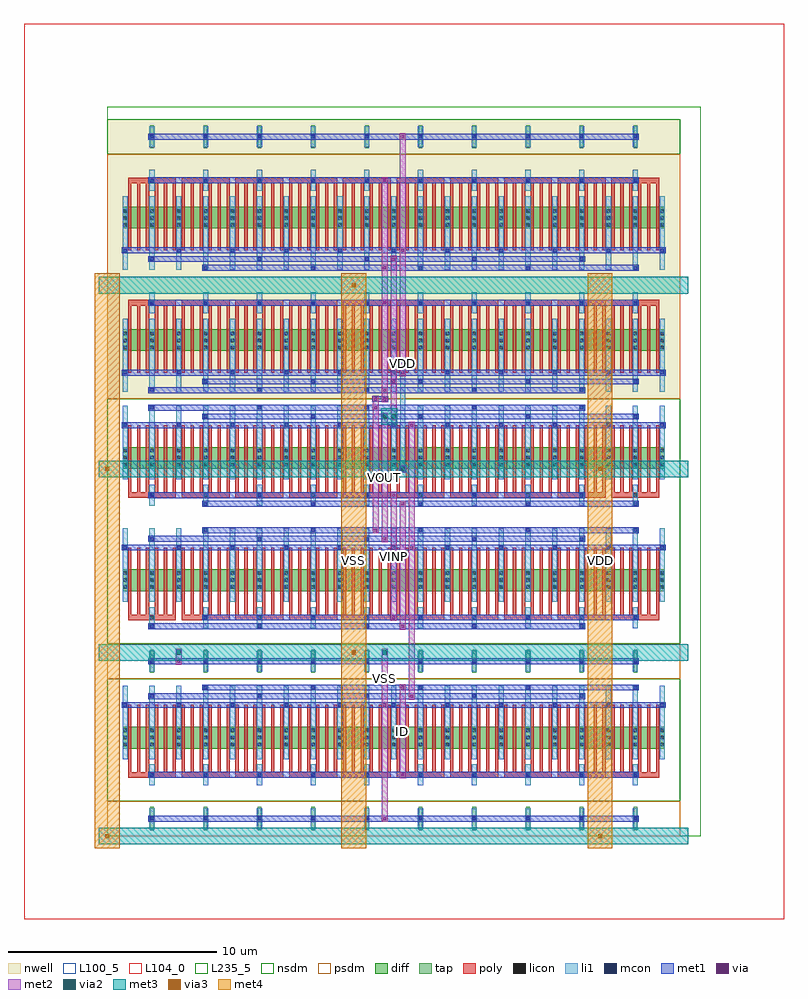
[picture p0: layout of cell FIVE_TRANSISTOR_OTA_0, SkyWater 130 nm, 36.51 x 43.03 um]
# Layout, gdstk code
from math import pi, radians
import gdstk
lib = gdstk.Library(unit=1e-6, precision=1e-09)
def R(c, l, rs):  # rectangles x0, y0, x1, y1
    for r in rs: c.add(gdstk.rectangle(r[:2], r[2:], *l))
def A(c, l, x, y, w, h, nx, ny, dx, dy):  # array of equal rectangles
    R(c, l, [(x+i*dx, y+j*dy, x+i*dx+w, y+j*dy+h) for i in range(nx) for j in range(ny)])
def P(c, l, *ps):  # polygons
    for p in ps: c.add(gdstk.Polygon(p, *l))
nwell = (64, 20)
diff = (65, 20)
tap = (65, 44)
poly = (66, 20)
licon = (66, 44)
li1 = (67, 20)
mcon = (67, 44)
met1 = (68, 20)
via = (68, 44)
met2 = (69, 20)
via2 = (69, 44)
met3 = (70, 20)
via3 = (70, 44)
met4 = (71, 20)
nsdm = (93, 44)
psdm = (94, 20)
L100_5 = (100, 5)
L104_0 = (104, 0)
L235_5 = (235, 5)

scm_nmos_50859816_x5_y1_ = lib.new_cell('SCM_NMOS_50859816_X5_Y1_1676474433')
R(scm_nmos_50859816_x5_y1_, diff, [(0.735,2.31,26.785,3.36)])
A(scm_nmos_50859816_x5_y1_, tap, 2.065, 6.16, 0.17, 1.12, 10, 1, 2.58, 0)
A(scm_nmos_50859816_x5_y1_, poly, 1, 1.26, 0.15, 3.36, 60, 1, 0.43, 0)
A(scm_nmos_50859816_x5_y1_, poly, 1, 4.485, 2.3, 0.27, 10, 1, 2.58, 0)
A(scm_nmos_50859816_x5_y1_, licon, 0.775, 2.39, 0.17, 0.17, 3, 3, 1.29, 0.34)
A(scm_nmos_50859816_x5_y1_, licon, 3.355, 2.39, 0.17, 0.17, 3, 3, 1.29, 0.34)
A(scm_nmos_50859816_x5_y1_, licon, 5.935, 2.39, 0.17, 0.17, 3, 3, 1.29, 0.34)
A(scm_nmos_50859816_x5_y1_, licon, 8.515, 2.39, 0.17, 0.17, 3, 3, 1.29, 0.34)
A(scm_nmos_50859816_x5_y1_, licon, 11.095, 2.39, 0.17, 0.17, 3, 3, 1.29, 0.34)
A(scm_nmos_50859816_x5_y1_, licon, 13.675, 2.39, 0.17, 0.17, 3, 3, 1.29, 0.34)
A(scm_nmos_50859816_x5_y1_, licon, 16.255, 2.39, 0.17, 0.17, 3, 3, 1.29, 0.34)
A(scm_nmos_50859816_x5_y1_, licon, 18.835, 2.39, 0.17, 0.17, 3, 3, 1.29, 0.34)
A(scm_nmos_50859816_x5_y1_, licon, 21.415, 2.39, 0.17, 0.17, 3, 3, 1.29, 0.34)
A(scm_nmos_50859816_x5_y1_, licon, 23.995, 2.39, 0.17, 0.17, 3, 3, 1.29, 0.34)
A(scm_nmos_50859816_x5_y1_, licon, 2.065, 4.535, 0.17, 0.17, 10, 2, 2.58, 2.1)
A(scm_nmos_50859816_x5_y1_, li1, 0.735, 0.335, 0.25, 3.53, 21, 1, 1.29, 0)
A(scm_nmos_50859816_x5_y1_, li1, 2.025, 4.115, 0.25, 1.01, 10, 2, 2.58, 2.1)
A(scm_nmos_50859816_x5_y1_, mcon, 2.065, 0.335, 0.17, 0.17, 5, 1, 5.16, 0)
A(scm_nmos_50859816_x5_y1_, mcon, 4.645, 0.755, 0.17, 0.17, 5, 1, 5.16, 0)
A(scm_nmos_50859816_x5_y1_, mcon, 0.775, 1.175, 0.17, 0.17, 11, 1, 2.58, 0)
A(scm_nmos_50859816_x5_y1_, mcon, 2.065, 4.535, 0.17, 0.17, 10, 2, 2.58, 2.1)
R(scm_nmos_50859816_x5_y1_, met1, [(1.98,0.28,22.96,0.56), (4.56,0.7,25.54,0.98), (0.69,1.12,26.83,1.4), (1.98,4.48,25.54,4.76), (1.98,6.58,25.54,6.86)])
R(scm_nmos_50859816_x5_y1_, via, [(13.255,0.345,13.405,0.495), (14.115,1.185,14.265,1.335), (13.255,4.545,13.405,4.695), (14.115,6.645,14.265,6.795)])
R(scm_nmos_50859816_x5_y1_, met2, [(13.19,0.26,13.47,4.78), (14.05,1.1,14.33,6.88)])
R(scm_nmos_50859816_x5_y1_, nsdm, [(0,0,27.52,5.88)])
R(scm_nmos_50859816_x5_y1_, psdm, [(0,5.88,27.52,7.56)])
R(scm_nmos_50859816_x5_y1_, L100_5, [(0,0,27.52,7.56)])

scm_pmos_24041719_x5_y2_ = lib.new_cell('SCM_PMOS_24041719_X5_Y2_1676474434')
R(scm_pmos_24041719_x5_y2_, nwell, [(0,0,27.52,13.44)])
R(scm_pmos_24041719_x5_y2_, diff, [(0.735,2.31,26.785,3.36), (0.735,8.19,26.785,9.24)])
A(scm_pmos_24041719_x5_y2_, tap, 2.065, 12.04, 0.17, 1.12, 10, 1, 2.58, 0)
A(scm_pmos_24041719_x5_y2_, poly, 1, 1.26, 0.15, 3.36, 60, 2, 0.43, 5.88)
A(scm_pmos_24041719_x5_y2_, poly, 1, 4.485, 2.3, 0.27, 10, 2, 2.58, 5.88)
A(scm_pmos_24041719_x5_y2_, licon, 0.775, 2.39, 0.17, 0.17, 3, 3, 1.29, 0.34)
A(scm_pmos_24041719_x5_y2_, licon, 3.355, 2.39, 0.17, 0.17, 3, 3, 1.29, 0.34)
A(scm_pmos_24041719_x5_y2_, licon, 5.935, 2.39, 0.17, 0.17, 3, 3, 1.29, 0.34)
A(scm_pmos_24041719_x5_y2_, licon, 8.515, 2.39, 0.17, 0.17, 3, 3, 1.29, 0.34)
A(scm_pmos_24041719_x5_y2_, licon, 11.095, 2.39, 0.17, 0.17, 3, 3, 1.29, 0.34)
A(scm_pmos_24041719_x5_y2_, licon, 13.675, 2.39, 0.17, 0.17, 3, 3, 1.29, 0.34)
A(scm_pmos_24041719_x5_y2_, licon, 16.255, 2.39, 0.17, 0.17, 3, 3, 1.29, 0.34)
A(scm_pmos_24041719_x5_y2_, licon, 18.835, 2.39, 0.17, 0.17, 3, 3, 1.29, 0.34)
A(scm_pmos_24041719_x5_y2_, licon, 21.415, 2.39, 0.17, 0.17, 3, 3, 1.29, 0.34)
A(scm_pmos_24041719_x5_y2_, licon, 23.995, 2.39, 0.17, 0.17, 3, 3, 1.29, 0.34)
A(scm_pmos_24041719_x5_y2_, licon, 2.065, 4.535, 0.17, 0.17, 10, 2, 2.58, 5.88)
A(scm_pmos_24041719_x5_y2_, licon, 0.775, 8.27, 0.17, 0.17, 3, 3, 1.29, 0.34)
A(scm_pmos_24041719_x5_y2_, licon, 3.355, 8.27, 0.17, 0.17, 3, 3, 1.29, 0.34)
A(scm_pmos_24041719_x5_y2_, licon, 5.935, 8.27, 0.17, 0.17, 3, 3, 1.29, 0.34)
A(scm_pmos_24041719_x5_y2_, licon, 8.515, 8.27, 0.17, 0.17, 3, 3, 1.29, 0.34)
A(scm_pmos_24041719_x5_y2_, licon, 11.095, 8.27, 0.17, 0.17, 3, 3, 1.29, 0.34)
A(scm_pmos_24041719_x5_y2_, licon, 13.675, 8.27, 0.17, 0.17, 3, 3, 1.29, 0.34)
A(scm_pmos_24041719_x5_y2_, licon, 16.255, 8.27, 0.17, 0.17, 3, 3, 1.29, 0.34)
A(scm_pmos_24041719_x5_y2_, licon, 18.835, 8.27, 0.17, 0.17, 3, 3, 1.29, 0.34)
A(scm_pmos_24041719_x5_y2_, licon, 21.415, 8.27, 0.17, 0.17, 3, 3, 1.29, 0.34)
A(scm_pmos_24041719_x5_y2_, licon, 23.995, 8.27, 0.17, 0.17, 3, 3, 1.29, 0.34)
R(scm_pmos_24041719_x5_y2_, licon, [(2.065,12.515,2.235,12.685), (2.065,12.515,2.235,12.685), (4.645,12.515,4.815,12.685), (4.645,12.515,4.815,12.685), (7.225,12.515,7.395,12.685), (7.225,12.515,7.395,12.685), (9.805,12.515,9.975,12.685), (9.805,12.515,9.975,12.685), (12.385,12.515,12.555,12.685), (12.385,12.515,12.555,12.685), (14.965,12.515,15.135,12.685), (14.965,12.515,15.135,12.685), (17.545,12.515,17.715,12.685), (17.545,12.515,17.715,12.685), (20.125,12.515,20.295,12.685), (20.125,12.515,20.295,12.685), (22.705,12.515,22.875,12.685), (22.705,12.515,22.875,12.685), (25.285,12.515,25.455,12.685), (25.285,12.515,25.455,12.685)])
A(scm_pmos_24041719_x5_y2_, li1, 0.735, 0.335, 0.25, 3.53, 21, 2, 1.29, 5.88)
A(scm_pmos_24041719_x5_y2_, li1, 2.025, 4.115, 0.25, 1.01, 10, 2, 2.58, 5.88)
A(scm_pmos_24041719_x5_y2_, li1, 2.025, 12.095, 0.25, 1.01, 10, 1, 2.58, 0)
A(scm_pmos_24041719_x5_y2_, mcon, 2.065, 0.335, 0.17, 0.17, 5, 2, 5.16, 6.3)
A(scm_pmos_24041719_x5_y2_, mcon, 4.645, 0.755, 0.17, 0.17, 5, 2, 5.16, 5.46)
A(scm_pmos_24041719_x5_y2_, mcon, 0.775, 1.175, 0.17, 0.17, 11, 2, 2.58, 5.88)
A(scm_pmos_24041719_x5_y2_, mcon, 2.065, 4.535, 0.17, 0.17, 10, 2, 2.58, 5.88)
A(scm_pmos_24041719_x5_y2_, mcon, 2.065, 12.515, 0.17, 0.17, 10, 1, 2.58, 0)
R(scm_pmos_24041719_x5_y2_, met1, [(1.98,0.28,22.96,0.56), (4.56,0.7,25.54,0.98), (0.69,1.12,26.83,1.4), (1.98,4.48,25.54,4.76), (4.56,6.16,25.54,6.44), (1.98,6.58,22.96,6.86), (0.69,7,26.83,7.28), (1.98,10.36,25.54,10.64), (1.98,12.46,25.54,12.74)])
R(scm_pmos_24041719_x5_y2_, via, [(13.255,0.345,13.405,0.495), (13.685,0.765,13.835,0.915), (14.115,1.185,14.265,1.335), (13.255,4.545,13.405,4.695), (13.255,6.225,13.405,6.375), (13.685,6.645,13.835,6.795), (14.115,7.065,14.265,7.215), (13.255,10.425,13.405,10.575), (14.115,12.525,14.265,12.675)])
R(scm_pmos_24041719_x5_y2_, met2, [(13.19,0.26,13.47,10.66), (13.62,0.68,13.9,6.88), (14.05,1.1,14.33,12.76)])
R(scm_pmos_24041719_x5_y2_, nsdm, [(0,11.76,27.52,13.44)])
R(scm_pmos_24041719_x5_y2_, psdm, [(0,0,27.52,11.76)])
R(scm_pmos_24041719_x5_y2_, L100_5, [(0,0,27.52,13.44)])

dp_nmos_b_62677564_x5_y2 = lib.new_cell('DP_NMOS_B_62677564_X5_Y2_1676474432')
R(dp_nmos_b_62677564_x5_y2, diff, [(0.735,2.31,26.785,3.36), (0.735,8.19,26.785,9.24)])
A(dp_nmos_b_62677564_x5_y2, tap, 2.065, 12.04, 0.17, 1.12, 10, 1, 2.58, 0)
A(dp_nmos_b_62677564_x5_y2, poly, 1, 1.26, 0.15, 3.36, 60, 2, 0.43, 5.88)
A(dp_nmos_b_62677564_x5_y2, poly, 1, 4.485, 2.3, 0.27, 10, 2, 2.58, 5.88)
A(dp_nmos_b_62677564_x5_y2, licon, 0.775, 2.39, 0.17, 0.17, 3, 3, 1.29, 0.34)
A(dp_nmos_b_62677564_x5_y2, licon, 3.355, 2.39, 0.17, 0.17, 3, 3, 1.29, 0.34)
A(dp_nmos_b_62677564_x5_y2, licon, 5.935, 2.39, 0.17, 0.17, 3, 3, 1.29, 0.34)
A(dp_nmos_b_62677564_x5_y2, licon, 8.515, 2.39, 0.17, 0.17, 3, 3, 1.29, 0.34)
A(dp_nmos_b_62677564_x5_y2, licon, 11.095, 2.39, 0.17, 0.17, 3, 3, 1.29, 0.34)
A(dp_nmos_b_62677564_x5_y2, licon, 13.675, 2.39, 0.17, 0.17, 3, 3, 1.29, 0.34)
A(dp_nmos_b_62677564_x5_y2, licon, 16.255, 2.39, 0.17, 0.17, 3, 3, 1.29, 0.34)
A(dp_nmos_b_62677564_x5_y2, licon, 18.835, 2.39, 0.17, 0.17, 3, 3, 1.29, 0.34)
A(dp_nmos_b_62677564_x5_y2, licon, 21.415, 2.39, 0.17, 0.17, 3, 3, 1.29, 0.34)
A(dp_nmos_b_62677564_x5_y2, licon, 23.995, 2.39, 0.17, 0.17, 3, 3, 1.29, 0.34)
A(dp_nmos_b_62677564_x5_y2, licon, 2.065, 4.535, 0.17, 0.17, 10, 2, 2.58, 5.88)
A(dp_nmos_b_62677564_x5_y2, licon, 0.775, 8.27, 0.17, 0.17, 3, 3, 1.29, 0.34)
A(dp_nmos_b_62677564_x5_y2, licon, 3.355, 8.27, 0.17, 0.17, 3, 3, 1.29, 0.34)
A(dp_nmos_b_62677564_x5_y2, licon, 5.935, 8.27, 0.17, 0.17, 3, 3, 1.29, 0.34)
A(dp_nmos_b_62677564_x5_y2, licon, 8.515, 8.27, 0.17, 0.17, 3, 3, 1.29, 0.34)
A(dp_nmos_b_62677564_x5_y2, licon, 11.095, 8.27, 0.17, 0.17, 3, 3, 1.29, 0.34)
A(dp_nmos_b_62677564_x5_y2, licon, 13.675, 8.27, 0.17, 0.17, 3, 3, 1.29, 0.34)
A(dp_nmos_b_62677564_x5_y2, licon, 16.255, 8.27, 0.17, 0.17, 3, 3, 1.29, 0.34)
A(dp_nmos_b_62677564_x5_y2, licon, 18.835, 8.27, 0.17, 0.17, 3, 3, 1.29, 0.34)
A(dp_nmos_b_62677564_x5_y2, licon, 21.415, 8.27, 0.17, 0.17, 3, 3, 1.29, 0.34)
A(dp_nmos_b_62677564_x5_y2, licon, 23.995, 8.27, 0.17, 0.17, 3, 3, 1.29, 0.34)
R(dp_nmos_b_62677564_x5_y2, licon, [(2.065,12.515,2.235,12.685), (2.065,12.515,2.235,12.685), (4.645,12.515,4.815,12.685), (4.645,12.515,4.815,12.685), (7.225,12.515,7.395,12.685), (7.225,12.515,7.395,12.685), (9.805,12.515,9.975,12.685), (9.805,12.515,9.975,12.685), (12.385,12.515,12.555,12.685), (12.385,12.515,12.555,12.685), (14.965,12.515,15.135,12.685), (14.965,12.515,15.135,12.685), (17.545,12.515,17.715,12.685), (17.545,12.515,17.715,12.685), (20.125,12.515,20.295,12.685), (20.125,12.515,20.295,12.685), (22.705,12.515,22.875,12.685), (22.705,12.515,22.875,12.685), (25.285,12.515,25.455,12.685), (25.285,12.515,25.455,12.685)])
A(dp_nmos_b_62677564_x5_y2, li1, 0.735, 0.335, 0.25, 3.53, 21, 2, 1.29, 5.88)
A(dp_nmos_b_62677564_x5_y2, li1, 2.025, 4.115, 0.25, 1.01, 10, 2, 2.58, 5.88)
A(dp_nmos_b_62677564_x5_y2, li1, 2.025, 12.095, 0.25, 1.01, 10, 1, 2.58, 0)
A(dp_nmos_b_62677564_x5_y2, mcon, 2.065, 0.335, 0.17, 0.17, 5, 2, 5.16, 4.2)
A(dp_nmos_b_62677564_x5_y2, mcon, 4.645, 0.755, 0.17, 0.17, 5, 2, 5.16, 4.2)
A(dp_nmos_b_62677564_x5_y2, mcon, 0.775, 1.175, 0.17, 0.17, 11, 2, 2.58, 5.88)
A(dp_nmos_b_62677564_x5_y2, mcon, 4.645, 6.215, 0.17, 0.17, 5, 2, 5.16, 4.2)
A(dp_nmos_b_62677564_x5_y2, mcon, 2.065, 6.635, 0.17, 0.17, 5, 2, 5.16, 4.2)
A(dp_nmos_b_62677564_x5_y2, mcon, 2.065, 12.515, 0.17, 0.17, 10, 1, 2.58, 0)
R(dp_nmos_b_62677564_x5_y2, met1, [(1.98,0.28,22.96,0.56), (4.56,0.7,25.54,0.98), (0.69,1.12,26.83,1.4), (1.98,4.48,22.96,4.76), (4.56,4.9,25.54,5.18), (4.56,6.16,25.54,6.44), (1.98,6.58,22.96,6.86), (0.69,7,26.83,7.28), (4.56,10.36,25.54,10.64), (1.98,10.78,22.96,11.06), (1.98,12.46,25.54,12.74)])
R(dp_nmos_b_62677564_x5_y2, via, [(12.825,0.345,12.975,0.495), (13.255,0.765,13.405,0.915), (14.545,1.185,14.695,1.335), (13.685,4.545,13.835,4.695), (14.115,4.965,14.265,5.115), (12.825,6.225,12.975,6.375), (13.255,6.645,13.405,6.795), (14.545,7.065,14.695,7.215), (13.685,10.425,13.835,10.575), (14.115,10.845,14.265,10.995)])
R(dp_nmos_b_62677564_x5_y2, met2, [(12.76,0.26,13.04,6.46), (13.19,0.68,13.47,6.88), (14.48,1.1,14.76,7.3), (13.62,4.46,13.9,10.66), (14.05,4.88,14.33,11.08)])
R(dp_nmos_b_62677564_x5_y2, nsdm, [(0,0,27.52,11.76)])
R(dp_nmos_b_62677564_x5_y2, psdm, [(0,11.76,27.52,13.44)])
R(dp_nmos_b_62677564_x5_y2, L100_5, [(0,0,27.52,13.44)])

five_transistor_ota_0 = lib.new_cell('FIVE_TRANSISTOR_OTA_0')
R(five_transistor_ota_0, li1, [(14.065,17.555,14.315,17.725), (14.065,17.64,14.315,22.68), (14.065,22.595,14.315,22.765)])
R(five_transistor_ota_0, mcon, [(14.105,17.555,14.275,17.725), (14.105,22.595,14.275,22.765)])
R(five_transistor_ota_0, met1, [(14.46,6.58,14.78,6.86), (14.46,6.58,14.78,6.86), (3.28,8.26,3.6,8.54), (3.28,8.26,3.6,8.54), (14.02,17.5,14.36,17.78), (14.03,17.5,14.35,17.78), (14.041,17.5,14.339,17.78), (12.74,20.86,13.06,21.14), (12.74,20.86,13.06,21.14), (12.9,20.86,13.33,21.14), (13.17,20.86,13.49,21.14), (13.17,20.86,13.49,21.14), (14.02,22.54,14.36,22.82), (14.03,22.54,14.35,22.82), (14.041,22.54,14.339,22.82)])
P(five_transistor_ota_0, met1, [(0,0),(0,0),(0,0),(0,0)],
  [(0,0),(0,0),(0,0),(0,0)])
R(five_transistor_ota_0, via, [(14.545,6.645,14.695,6.795), (14.545,6.645,14.695,6.795), (3.365,8.325,3.515,8.475), (3.365,8.325,3.515,8.475), (14.115,17.565,14.265,17.715), (12.825,20.925,12.975,21.075), (12.825,20.925,12.975,21.075), (13.255,20.925,13.405,21.075), (13.255,20.925,13.405,21.075), (14.115,22.605,14.265,22.755)])
R(five_transistor_ota_0, met2, [(13.19,6.3,13.47,8.82), (14.48,6.56,14.76,6.88), (14.48,6.56,14.76,6.88), (14.48,6.72,14.76,13.86), (3.3,8.24,3.58,8.56), (3.3,8.24,3.58,8.56), (3.3,8.4,3.58,8.82), (3.3,8.635,3.58,9.005), (3.3,8.635,3.58,9.005), (13.19,8.635,13.47,9.005), (13.19,8.635,13.47,9.005), (13.19,8.635,13.47,9.005), (14.05,17.455,14.33,17.825), (14.05,17.48,14.33,17.8), (14.05,17.519,14.33,17.761), (13.19,19.975,13.47,20.345), (13.19,19.975,13.47,20.345), (13.62,19.975,13.9,20.345), (13.62,19.975,13.9,20.345), (13.62,20.16,13.9,21.84), (12.76,20.58,13.04,21), (12.76,20.84,13.04,21.16), (12.76,20.84,13.04,21.16), (13.19,20.84,13.47,21.16), (13.19,20.84,13.47,21.16), (13.19,21,13.47,21.42), (14.05,22.52,14.33,22.84)])
P(five_transistor_ota_0, met2, [(0,0),(0,0),(0,0),(0,0)],
  [(0,0),(0,0),(0,0),(0,0)],
  [(0,0),(0,0),(0,0),(0,0)],
  [(0,0),(0,0),(0,0),(0,0)],
  [(0,0),(0,0),(0,0),(0,0)],
  [(0,0),(0,0),(0,0),(0,0)],
  [(0,0),(0,0),(0,0),(0,0)],
  [(0,0),(0,0),(0,0),(0,0)],
  [(0,0),(0,0),(0,0),(0,0)],
  [(0,0),(0,0),(0,0),(0,0)],
  [(0,0),(0,0),(0,0),(0,0)],
  [(0,0),(0,0),(0,0),(0,0)],
  [(0,0),(0,0),(0,0),(0,0)],
  [(0,0),(0,0),(0,0),(0,0)])
R(five_transistor_ota_0, via2, [(3.34,8.72,3.54,8.92), (3.34,8.72,3.54,8.92), (13.23,8.72,13.43,8.92), (13.23,8.72,13.43,8.92), (13.23,8.72,13.43,8.92), (14.09,17.54,14.29,17.74), (13.23,20.06,13.43,20.26), (13.23,20.06,13.43,20.26), (13.66,20.06,13.86,20.26), (13.66,20.06,13.86,20.26)])
A(five_transistor_ota_0, met3, -0.4, -0.4, 4.24, 0.8, 3, 4, 3.44, 8.82)
A(five_transistor_ota_0, met3, 9.92, -0.4, 2.32, 0.8, 1, 4, 0, 8.82)
A(five_transistor_ota_0, met3, 11.44, -0.4, 2.72, 0.8, 1, 4, 0, 8.82)
A(five_transistor_ota_0, met3, 13.36, -0.4, 4.24, 0.8, 1, 4, 0, 8.82)
A(five_transistor_ota_0, met3, 16.8, -0.4, 4.24, 0.8, 1, 4, 0, 8.82)
A(five_transistor_ota_0, met3, 20.24, -0.4, 3.84, 0.8, 1, 4, 0, 8.82)
A(five_transistor_ota_0, met3, 23.28, -0.4, 1.2, 0.8, 1, 4, 0, 8.82)
A(five_transistor_ota_0, met3, 23.68, -0.4, 4.24, 0.8, 1, 4, 0, 8.82)
R(five_transistor_ota_0, met3, [(-0.165,-0.4,0.165,0.4), (23.515,-0.4,23.845,0.4), (3.275,8.42,3.605,9.22), (3.275,8.42,3.605,9.22), (11.675,8.42,12.005,9.22), (13.165,8.42,13.495,9.22), (13.165,8.42,13.495,9.22), (13.165,8.42,13.495,9.22), (-0.165,17.24,0.165,18.04), (14.025,17.24,14.355,18.04), (23.515,17.24,23.845,18.04), (13.165,19.76,13.495,20.56), (13.165,19.76,13.495,20.56), (13.33,19.76,13.76,20.56), (13.595,19.76,13.925,20.56), (13.595,19.76,13.925,20.56), (11.675,26.06,12.005,26.86)])
R(five_transistor_ota_0, via3, [(-0.1,-0.1,0.1,0.1), (23.58,-0.1,23.78,0.1), (11.74,8.72,11.94,8.92), (-0.1,17.54,0.1,17.74), (23.58,17.54,23.78,17.74), (11.74,26.36,11.94,26.56)])
A(five_transistor_ota_0, met4, -0.59, -0.59, 1.18, 10, 3, 3, 11.84, 8.82)
R(five_transistor_ota_0, met4, [(-0.59,-0.165,0.59,0.165), (23.09,-0.165,24.27,0.165), (11.25,8.655,12.43,8.985), (-0.59,17.475,0.59,17.805), (23.09,17.475,24.27,17.805), (11.25,26.295,12.43,26.625)])
R(five_transistor_ota_0, L104_0, [(-4,-4,32.51,39.03)])
R(five_transistor_ota_0, L235_5, [(0,0,28.51,35.03)])
five_transistor_ota_0.add(gdstk.Reference(scm_nmos_50859816_x5_y1_, (27.52,7.56), rotation=pi))
five_transistor_ota_0.add(gdstk.Reference(scm_pmos_24041719_x5_y2_, (0,21)))
five_transistor_ota_0.add(gdstk.Reference(dp_nmos_b_62677564_x5_y2, (0,21), x_reflection=True))
five_transistor_ota_0.add(gdstk.Label('ID', (14.19,5.04), layer=69, texttype=5))
five_transistor_ota_0.add(gdstk.Label('VOUT', (13.33,17.22), layer=69, texttype=5))
five_transistor_ota_0.add(gdstk.Label('VINP', (13.76,13.44), layer=69, texttype=5))
five_transistor_ota_0.add(gdstk.Label('VINN', (14.19,13.02), layer=69, texttype=5))
five_transistor_ota_0.add(gdstk.Label('VSS', (13.33,7.56), layer=69, texttype=5))
five_transistor_ota_0.add(gdstk.Label('VSS', (11.84,13.23), layer=71, texttype=5))
five_transistor_ota_0.add(gdstk.Label('VSS', (11.84,13.23), layer=71, texttype=5))
five_transistor_ota_0.add(gdstk.Label('VSS', (11.84,13.23), layer=71, texttype=5))
five_transistor_ota_0.add(gdstk.Label('VSS', (11.84,13.23), layer=71, texttype=5))
five_transistor_ota_0.add(gdstk.Label('VSS', (11.84,13.23), layer=71, texttype=5))
five_transistor_ota_0.add(gdstk.Label('VDD', (23.68,13.23), layer=71, texttype=5))
five_transistor_ota_0.add(gdstk.Label('VDD', (14.19,22.68), layer=68, texttype=5))
five_transistor_ota_0.add(gdstk.Label('VDD', (23.68,13.23), layer=71, texttype=5))
five_transistor_ota_0.add(gdstk.Label('VDD', (23.68,13.23), layer=71, texttype=5))
five_transistor_ota_0.add(gdstk.Label('VDD', (23.68,13.23), layer=71, texttype=5))
five_transistor_ota_0.add(gdstk.Label('VDD', (23.68,13.23), layer=71, texttype=5))
five_transistor_ota_0.add(gdstk.Label('VDD', (23.68,13.23), layer=71, texttype=5))

lib.write_gds('FIVE_TRANSISTOR_OTA_0.gds')
